| IBIS file chip.ibs created by s2ibis2 version 1.1
| North Carolina State University Electronics Research Laboratory  1995
[IBIS ver]   2.1
[File name]   chip.ibs
[File Rev]   0
[Date]   April 1, 2001
[Source]   From MegaFLOPS Inc. layout and silicon models.
[Notes]   This is not an actual device. No one would buy it anyway.
[Disclaimer]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
[Copyright]   Copyright 2001 MegaFLOPS Inc.
|   Component MCM Driver Chip
[Component]   MCM Driver Chip
[Manufacturer]   MegaFLOPS Inc.
[Package]
| variable   typ   min   max
R_pkg   2.00m   1.00m   4.00m
L_pkg   0.20nH   0.10nH   0.40nH
C_pkg   2.00pF   1.00pF   4.00pF
[Pin]  signal_name   model_name   R_pin   L_pin   C_pin
1   gnd   GND
2   in1   input   5.00m   8.00nH   3.00pF
3   in2   input
4   in3   input
5   enable   input
6   NC   NC
7   out3   driver
8   out2   tristate_driver
9   out1   tristate_driver
10   vdd   POWER
| Models and submodels in the file (3): input (Input), driver (Output), tristate_driver (3-state)
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|   Model input
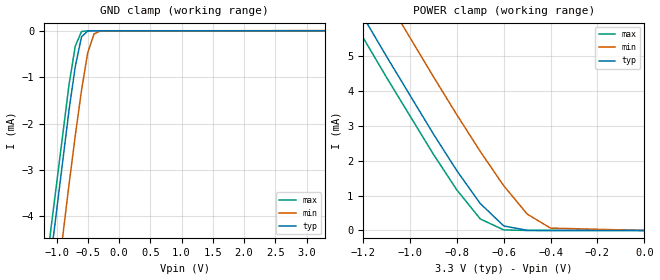
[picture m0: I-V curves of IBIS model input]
[Model]   input
Model_type   Input
C_comp   5.00pF   5.00pF   5.00pF
[Temperature Range]   27.00   100.00   0.000
[Voltage Range]   3.30V   3.00V   3.60V
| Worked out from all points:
|   GND clamp passes 1 mA (typ) near -0.72 V on its own axis
|   POWER clamp passes 1 mA (typ) near -0.72 V on its own axis
[GND_clamp]
| voltage   I(typ)   I(min)   I(max)
-3.3V     -30.81mA   -32.43mA   -30.24mA
-1.4V     -8.42mA    -10.08mA   -7.82mA
-1.3V     -7.26mA    -8.93mA    -6.66mA
-1.2V     -6.12mA    -7.78mA    -5.52mA
-1.1V     -4.98mA    -6.64mA    -4.38mA
-800mV    -1.71mA    -3.31mA    -1.16mA
-700mV    -770uA     -2.26mA    -330uA
-600mV    -130uA     -1.28mA    -16.45uA
-500mV    -4.84uA    -470uA     -260nA
-400mV    -100nA     -67.71uA   -3.71nA
-300mV    -2.19nA    -3.88uA    -61.31pA
3.3V      6.62pA     3.88uA     6pA
[POWER_clamp]
| voltage   I(typ)   I(min)   I(max)
-3.3V     30.81mA    32.43mA    30.24mA
-1.4V     8.42mA     10.08mA    7.82mA
-1.3V     7.26mA     8.93mA     6.66mA
-1.2V     6.12mA     7.78mA     5.52mA
-1.1V     4.98mA     6.64mA     4.38mA
-900mV    2.76mA     4.4mA      2.18mA
-800mV    1.71mA     3.31mA     1.16mA
-700mV    770uA      2.26mA     330uA
-600mV    130uA      1.28mA     16.45uA
-500mV    4.84uA     470uA      260nA
-400mV    100nA      67.71uA    3.71nA
0V        6.62pA     360pA      7.2pA
|   Model driver
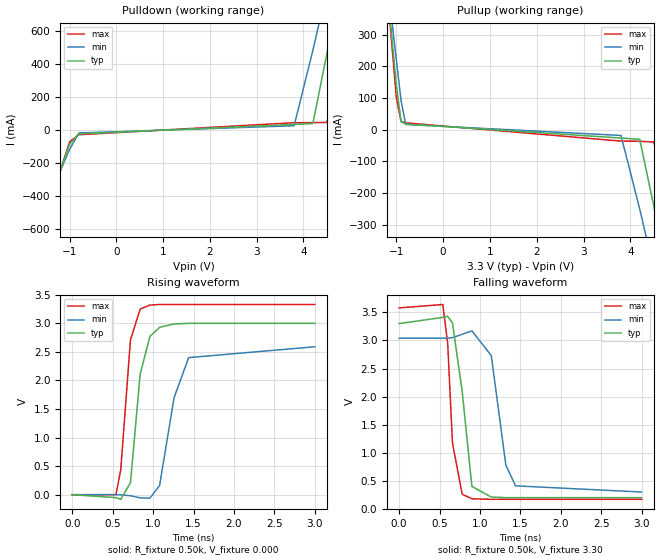
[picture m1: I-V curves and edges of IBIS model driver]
[Model]   driver
Model_type   Output
Polarity   Non-Inverting
C_comp   5.00pF   5.00pF   5.00pF
[Temperature Range]   27.00   100.00   0.000
[Voltage Range]   3.30V   3.00V   3.60V
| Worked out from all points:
|   slope of the pulldown table from 0 to 0.495 V, typ, clamps not added: 35.6 ohm
|   slope of the pullup table from 0 to 0.495 V, typ, clamps not added: 53 ohm
|   rising waveform, R_fixture 0.50k, V_fixture 0.000: 20-80 % time 135ps typ, 201ps min, 106ps max; typ from 0 V to 3 V
|   falling waveform, R_fixture 0.50k, V_fixture 3.30: 20-80 % time 98.8ps typ, 149ps min, 82.1ps max; typ from 3.3 V to 0.2 V
[Pulldown]
| voltage   I(typ)   I(min)   I(max)
-3.3V     -1.94A     -1.61A     -2.12A
-1.9V     -820mA     -710mA     -880mA
-1.7V     -660mA     -580mA     -700mA
-1V       -88.37mA   -120mA     -73.56mA
-800mV    -25.22mA   -19.48mA   -30.35mA
3.8V      32.13mA    24.11mA    42.78mA
4.2V      37.65mA    480mA      42.95mA
4.5V      460mA      850mA      44.43mA
4.7V      770mA      1.11A      290mA
4.9V      1.09A      1.36A      630mA
5.1V      1.4A       1.61A      980mA
6.6V      3.77A      3.52A      3.58A
[Pullup]
| voltage   I(typ)   I(min)   I(max)
-3.3V     3.79A      3.15A      4.12A
-1.5V     930mA      860mA      970mA
-1V       140mA      220mA      99.36mA
-900mV    25.45mA    91.47mA    25.83mA
-800mV    17.99mA    16.67mA    21.79mA
3.8V      -26.13mA   -17.99mA   -35.82mA
4.2V      -30.23mA   -250mA     -36.44mA
4.5V      -240mA     -440mA     -38.62mA
4.7V      -400mA     -570mA     -160mA
4.9V      -560mA     -700mA     -340mA
5.1V      -720mA     -820mA     -510mA
6.6V      -1.92A     -1.79A     -1.83A
[Ramp]
| variable   typ   min   max
dV/dt_r   1.80/0.11n   1.55/0.18n   2.00/88.89p
dV/dt_f   1.86/90.03p   1.64/0.15n   2.05/70.15p
R_load = 0.50k
[Rising Waveform]
R_fixture = 0.50k
V_fixture = 0.000
| time   V(typ)   V(min)   V(max)
0s        74.28uV    85.02uV    64.8uV
540ps     -50.67mV   1.23mV     -1.15mV
600ps     -81.12mV   -2.84mV    440mV
720ps     210mV      -18.27mV   2.71V
840ps     2.11V      -55.03mV   3.25V
960ps     2.77V      -60.96mV   3.32V
1.08ns    2.93V      160mV      3.33V
1.26ns    2.99V      1.7V       3.33V
1.44ns    3V         2.4V       3.33V
3ns       3V         2.59V      3.33V
[Falling Waveform]
R_fixture = 0.50k
V_fixture = 3.30
| time   V(typ)   V(min)   V(max)
0s        3.3V       3.04V      3.58V
540ps     3.41V      3.04V      3.64V
600ps     3.43V      3.04V      2.96V
660ps     3.31V      3.05V      1.17V
780ps     2.09V      3.11V      260mV
900ps     400mV      3.17V      180mV
1.14ns    210mV      2.73V      170mV
1.32ns    200mV      780mV      170mV
1.44ns    200mV      410mV      170mV
3ns       200mV      300mV      170mV
|   Model tristate_driver
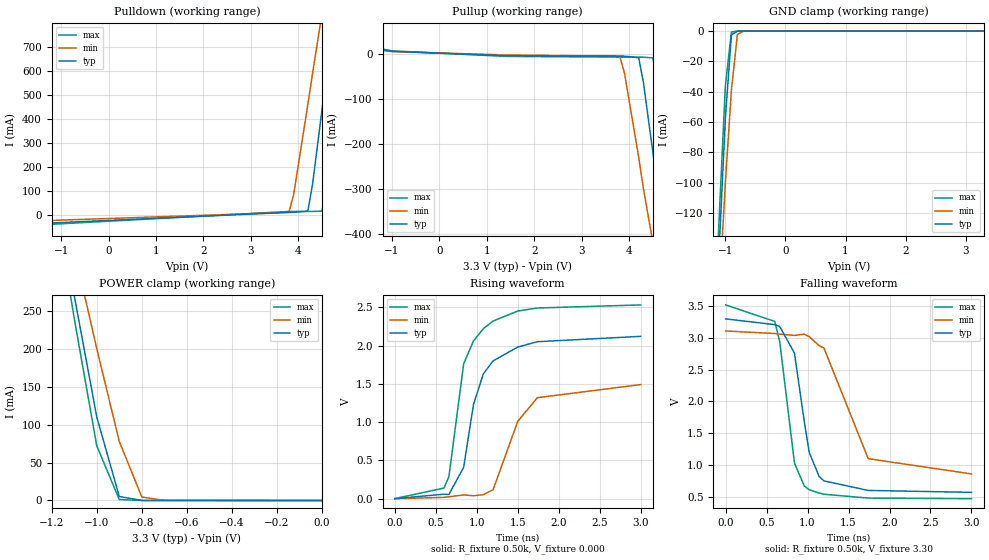
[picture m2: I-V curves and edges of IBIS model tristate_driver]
[Model]   tristate_driver
Model_type   3-state
Polarity   Non-Inverting
Enable   Active-Low
C_comp   5.00pF   5.00pF   5.00pF
[Temperature Range]   27.00   100.00   0.000
[Voltage Range]   3.30V   3.00V   3.60V
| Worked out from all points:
|   slope of the pulldown table from 0 to 0.495 V, typ, clamps not added: 102 ohm
|   slope of the pullup table from 0 to 0.495 V, typ, clamps not added: 229 ohm
|   GND clamp passes 1 mA (typ) near -0.84 V on its own axis
|   POWER clamp passes 1 mA (typ) near -0.82 V on its own axis
|   rising waveform, R_fixture 0.50k, V_fixture 0.000: 20-80 % time 278ps typ, 346ps min, 250ps max; typ from 0.002 V to 2.12 V
|   falling waveform, R_fixture 0.50k, V_fixture 3.30: 20-80 % time 201ps typ, 373ps min, 171ps max; typ from 3.3 V to 0.57 V
[Pulldown]
| voltage   I(typ)   I(min)   I(max)
-3.3V     -8.15mA    -3.31mA    -9.47mA
-2.9V     -7.23mA    -3.43mA    -56.79mA
-2.7V     -45.32mA   -31.67mA   -53.63mA
3.8V      11.72mA    11.67mA    15.66mA
3.9V      11.73mA    84.95mA    15.68mA
4.2V      17.13mA    460mA      15.72mA
4.3V      130mA      590mA      15.74mA
4.5V      440mA      840mA      17.16mA
4.7V      750mA      1.09A      260mA
4.9V      1.07A      1.35A      610mA
5.1V      1.38A      1.6A       950mA
6.6V      3.74A      3.5A       3.54A
[Pullup]
| voltage   I(typ)   I(min)   I(max)
-3.3V     44.21mA    32.14mA    52.15mA
-1V       5.21mA     4.54mA     6.16mA
1.4V      -4.72mA    -2.92mA    -6.11mA
3.8V      -5.59mA    -5.85mA    -7.73mA
3.9V      -5.62mA    -42.88mA   -7.74mA
4.2V      -9.1mA     -230mA     -7.79mA
4.3V      -64.3mA    -300mA     -7.93mA
4.5V      -220mA     -420mA     -9.41mA
4.7V      -380mA     -550mA     -130mA
4.9V      -540mA     -680mA     -310mA
5.1V      -700mA     -810mA     -480mA
6.6V      -1.89A     -1.77A     -1.79A
[GND_clamp]
| voltage   I(typ)   I(min)   I(max)
-3.3V     -1.88A     -1.57A     -2.04A
-1.2V     -210mA     -230mA     -210mA
-1.1V     -140mA     -170mA     -120mA
-1V       -57.32mA   -100mA     -36.14mA
-900mV    -2.63mA    -39mA      -630uA
-800mV    -55.14uA   -2.27mA    -9.15uA
-700mV    -1.16uA    -100uA     -140nA
3.3V      2.75pA     810pA      2.5pA
[POWER_clamp]
| voltage   I(typ)   I(min)   I(max)
-3.3V     3.73A      3.11A      4.05A
-1.2V     430mA      460mA      420mA
-1.1V     270mA      330mA      240mA
-1V       110mA      200mA      71.98mA
-900mV    5.24mA     77.73mA    1.26mA
-800mV    110uA      4.53mA     17.99uA
-700mV    2.3uA      200uA      260nA
0V        2.75pA     2.68pA     3pA
[Ramp]
| variable   typ   min   max
dV/dt_r   1.27/0.28n   0.89/0.37n   1.52/0.25n
dV/dt_f   1.64/0.20n   1.34/0.33n   1.85/0.15n
R_load = 0.50k
[Rising Waveform]
R_fixture = 0.50k
V_fixture = 0.000
| time   V(typ)   V(min)   V(max)
0s        2.09mV     1.32mV     2.55mV
600ps     59.92mV    18.72mV    140mV
660ps     56.1mV     26.13mV    290mV
840ps     410mV      50.69mV    1.76V
960ps     1.23V      39.36mV    2.06V
1.08ns    1.63V      53.27mV    2.22V
1.2ns     1.8V       120mV      2.32V
1.5ns     1.98V      1.01V      2.45V
1.74ns    2.05V      1.32V      2.49V
3ns       2.12V      1.49V      2.53V
[Falling Waveform]
R_fixture = 0.50k
V_fixture = 3.30
| time   V(typ)   V(min)   V(max)
0s        3.3V       3.11V      3.52V
600ps     3.21V      3.07V      3.26V
660ps     3.18V      3.06V      2.94V
840ps     2.76V      3.04V      1.03V
960ps     1.68V      3.06V      670mV
1.02ns    1.2V       3.02V      610mV
1.14ns    820mV      2.88V      560mV
1.2ns     750mV      2.84V      540mV
1.74ns    600mV      1.1V       480mV
3ns       570mV      860mV      470mV
